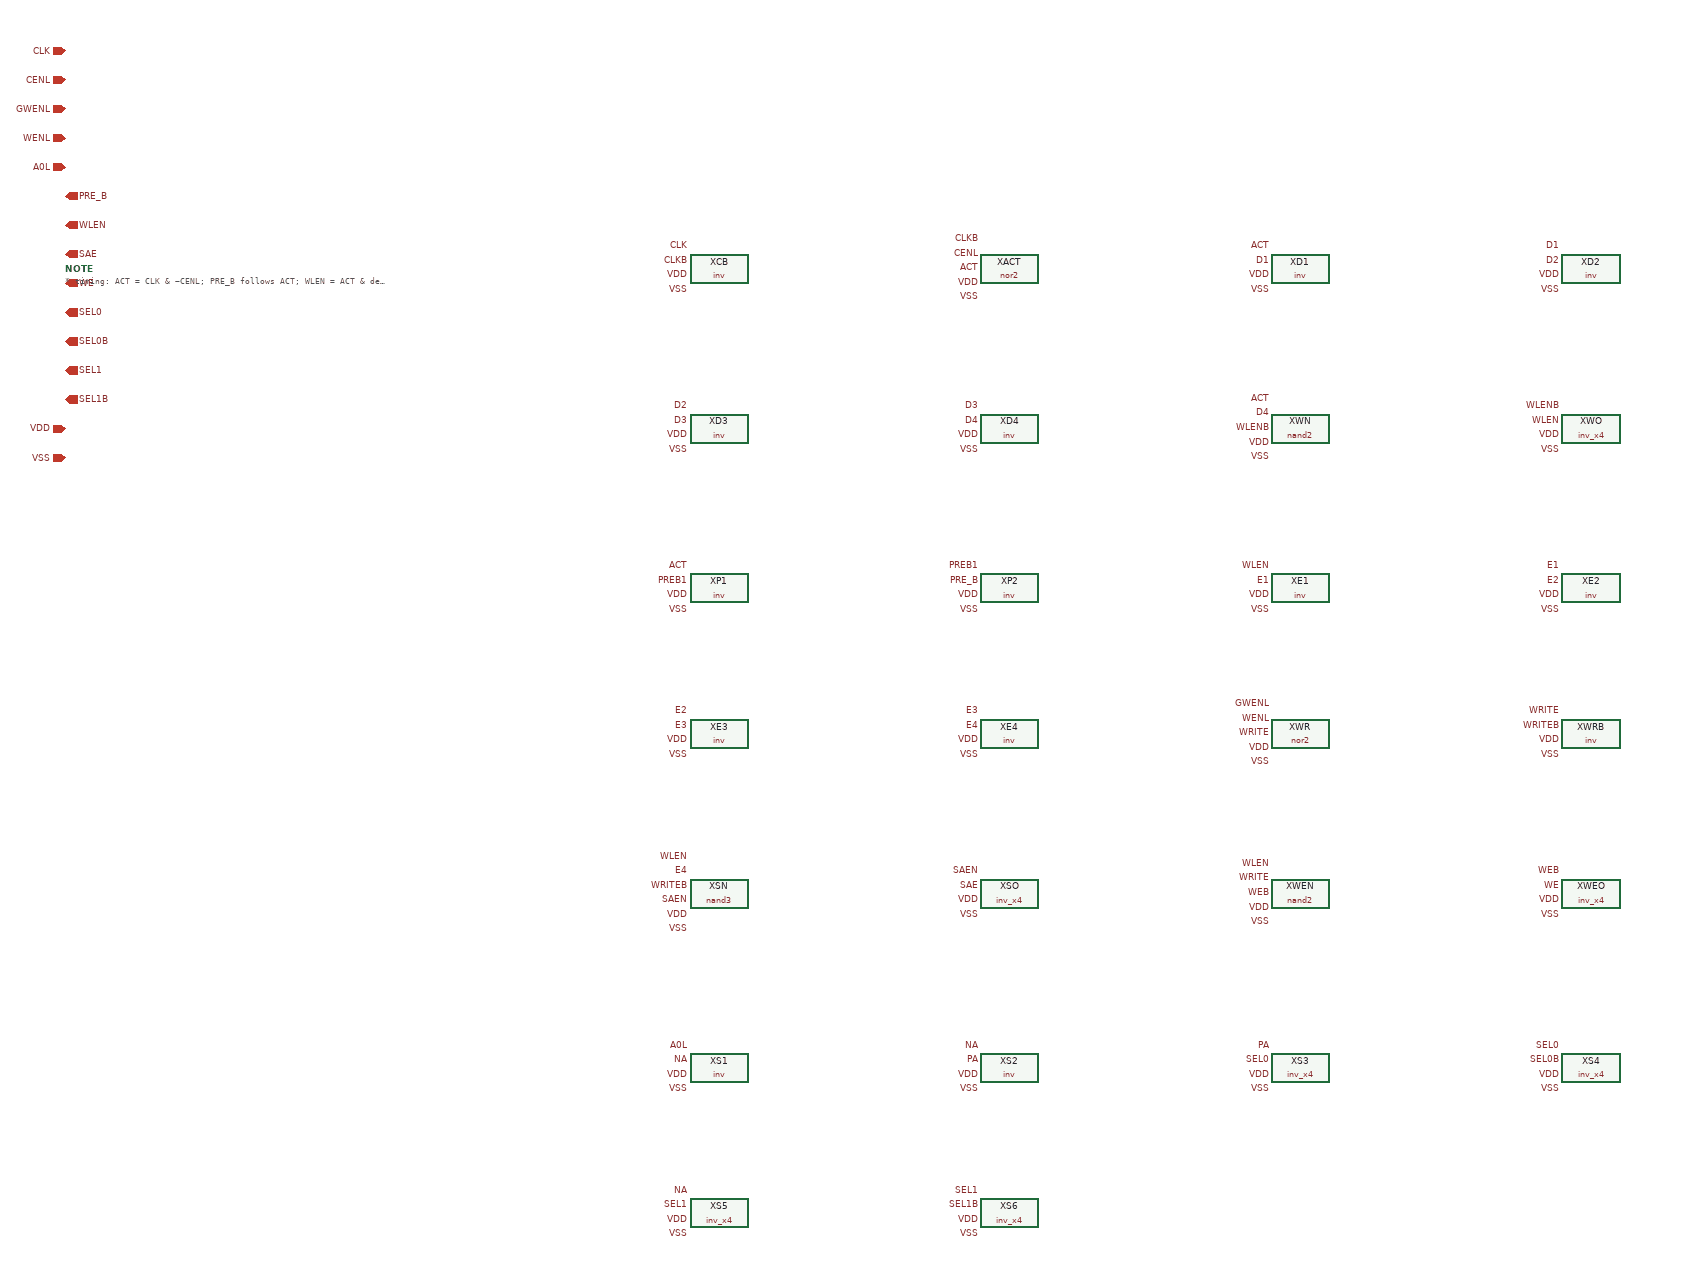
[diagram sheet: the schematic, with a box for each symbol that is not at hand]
v {xschem version=3.4.8RC file_version=1.3}
G {}
K {}
V {}
S {}
E {}
C {gates/inv.sym} 0 0 0 0 {name=XCB}
C {devices/lab_pin.sym} -40.0 -30.0 0 0 {name=l0 lab=CLK}
C {devices/lab_pin.sym} -40.0 -10.0 0 0 {name=l1 lab=CLKB}
C {devices/lab_pin.sym} -40.0 10.0 0 0 {name=l2 lab=VDD}
C {devices/lab_pin.sym} -40.0 30.0 0 0 {name=l3 lab=VSS}
C {gates/nor2.sym} 400 0 0 0 {name=XACT}
C {devices/lab_pin.sym} 360.0 -40.0 0 0 {name=l4 lab=CLKB}
C {devices/lab_pin.sym} 360.0 -20.0 0 0 {name=l5 lab=CENL}
C {devices/lab_pin.sym} 360.0 0.0 0 0 {name=l6 lab=ACT}
C {devices/lab_pin.sym} 360.0 20.0 0 0 {name=l7 lab=VDD}
C {devices/lab_pin.sym} 360.0 40.0 0 0 {name=l8 lab=VSS}
C {gates/inv.sym} 800 0 0 0 {name=XD1}
C {devices/lab_pin.sym} 760.0 -30.0 0 0 {name=l9 lab=ACT}
C {devices/lab_pin.sym} 760.0 -10.0 0 0 {name=l10 lab=D1}
C {devices/lab_pin.sym} 760.0 10.0 0 0 {name=l11 lab=VDD}
C {devices/lab_pin.sym} 760.0 30.0 0 0 {name=l12 lab=VSS}
C {gates/inv.sym} 1200 0 0 0 {name=XD2}
C {devices/lab_pin.sym} 1160.0 -30.0 0 0 {name=l13 lab=D1}
C {devices/lab_pin.sym} 1160.0 -10.0 0 0 {name=l14 lab=D2}
C {devices/lab_pin.sym} 1160.0 10.0 0 0 {name=l15 lab=VDD}
C {devices/lab_pin.sym} 1160.0 30.0 0 0 {name=l16 lab=VSS}
C {gates/inv.sym} 0 220 0 0 {name=XD3}
C {devices/lab_pin.sym} -40.0 190.0 0 0 {name=l17 lab=D2}
C {devices/lab_pin.sym} -40.0 210.0 0 0 {name=l18 lab=D3}
C {devices/lab_pin.sym} -40.0 230.0 0 0 {name=l19 lab=VDD}
C {devices/lab_pin.sym} -40.0 250.0 0 0 {name=l20 lab=VSS}
C {gates/inv.sym} 400 220 0 0 {name=XD4}
C {devices/lab_pin.sym} 360.0 190.0 0 0 {name=l21 lab=D3}
C {devices/lab_pin.sym} 360.0 210.0 0 0 {name=l22 lab=D4}
C {devices/lab_pin.sym} 360.0 230.0 0 0 {name=l23 lab=VDD}
C {devices/lab_pin.sym} 360.0 250.0 0 0 {name=l24 lab=VSS}
C {gates/nand2.sym} 800 220 0 0 {name=XWN}
C {devices/lab_pin.sym} 760.0 180.0 0 0 {name=l25 lab=ACT}
C {devices/lab_pin.sym} 760.0 200.0 0 0 {name=l26 lab=D4}
C {devices/lab_pin.sym} 760.0 220.0 0 0 {name=l27 lab=WLENB}
C {devices/lab_pin.sym} 760.0 240.0 0 0 {name=l28 lab=VDD}
C {devices/lab_pin.sym} 760.0 260.0 0 0 {name=l29 lab=VSS}
C {gates/inv_x4.sym} 1200 220 0 0 {name=XWO}
C {devices/lab_pin.sym} 1160.0 190.0 0 0 {name=l30 lab=WLENB}
C {devices/lab_pin.sym} 1160.0 210.0 0 0 {name=l31 lab=WLEN}
C {devices/lab_pin.sym} 1160.0 230.0 0 0 {name=l32 lab=VDD}
C {devices/lab_pin.sym} 1160.0 250.0 0 0 {name=l33 lab=VSS}
C {gates/inv.sym} 0 440 0 0 {name=XP1}
C {devices/lab_pin.sym} -40.0 410.0 0 0 {name=l34 lab=ACT}
C {devices/lab_pin.sym} -40.0 430.0 0 0 {name=l35 lab=PREB1}
C {devices/lab_pin.sym} -40.0 450.0 0 0 {name=l36 lab=VDD}
C {devices/lab_pin.sym} -40.0 470.0 0 0 {name=l37 lab=VSS}
C {gates/inv.sym} 400 440 0 0 {name=XP2}
C {devices/lab_pin.sym} 360.0 410.0 0 0 {name=l38 lab=PREB1}
C {devices/lab_pin.sym} 360.0 430.0 0 0 {name=l39 lab=PRE_B}
C {devices/lab_pin.sym} 360.0 450.0 0 0 {name=l40 lab=VDD}
C {devices/lab_pin.sym} 360.0 470.0 0 0 {name=l41 lab=VSS}
C {gates/inv.sym} 800 440 0 0 {name=XE1}
C {devices/lab_pin.sym} 760.0 410.0 0 0 {name=l42 lab=WLEN}
C {devices/lab_pin.sym} 760.0 430.0 0 0 {name=l43 lab=E1}
C {devices/lab_pin.sym} 760.0 450.0 0 0 {name=l44 lab=VDD}
C {devices/lab_pin.sym} 760.0 470.0 0 0 {name=l45 lab=VSS}
C {gates/inv.sym} 1200 440 0 0 {name=XE2}
C {devices/lab_pin.sym} 1160.0 410.0 0 0 {name=l46 lab=E1}
C {devices/lab_pin.sym} 1160.0 430.0 0 0 {name=l47 lab=E2}
C {devices/lab_pin.sym} 1160.0 450.0 0 0 {name=l48 lab=VDD}
C {devices/lab_pin.sym} 1160.0 470.0 0 0 {name=l49 lab=VSS}
C {gates/inv.sym} 0 640 0 0 {name=XE3}
C {devices/lab_pin.sym} -40.0 610.0 0 0 {name=l50 lab=E2}
C {devices/lab_pin.sym} -40.0 630.0 0 0 {name=l51 lab=E3}
C {devices/lab_pin.sym} -40.0 650.0 0 0 {name=l52 lab=VDD}
C {devices/lab_pin.sym} -40.0 670.0 0 0 {name=l53 lab=VSS}
C {gates/inv.sym} 400 640 0 0 {name=XE4}
C {devices/lab_pin.sym} 360.0 610.0 0 0 {name=l54 lab=E3}
C {devices/lab_pin.sym} 360.0 630.0 0 0 {name=l55 lab=E4}
C {devices/lab_pin.sym} 360.0 650.0 0 0 {name=l56 lab=VDD}
C {devices/lab_pin.sym} 360.0 670.0 0 0 {name=l57 lab=VSS}
C {gates/nor2.sym} 800 640 0 0 {name=XWR}
C {devices/lab_pin.sym} 760.0 600.0 0 0 {name=l58 lab=GWENL}
C {devices/lab_pin.sym} 760.0 620.0 0 0 {name=l59 lab=WENL}
C {devices/lab_pin.sym} 760.0 640.0 0 0 {name=l60 lab=WRITE}
C {devices/lab_pin.sym} 760.0 660.0 0 0 {name=l61 lab=VDD}
C {devices/lab_pin.sym} 760.0 680.0 0 0 {name=l62 lab=VSS}
C {gates/inv.sym} 1200 640 0 0 {name=XWRB}
C {devices/lab_pin.sym} 1160.0 610.0 0 0 {name=l63 lab=WRITE}
C {devices/lab_pin.sym} 1160.0 630.0 0 0 {name=l64 lab=WRITEB}
C {devices/lab_pin.sym} 1160.0 650.0 0 0 {name=l65 lab=VDD}
C {devices/lab_pin.sym} 1160.0 670.0 0 0 {name=l66 lab=VSS}
C {gates/nand3.sym} 0 860 0 0 {name=XSN}
C {devices/lab_pin.sym} -40.0 810.0 0 0 {name=l67 lab=WLEN}
C {devices/lab_pin.sym} -40.0 830.0 0 0 {name=l68 lab=E4}
C {devices/lab_pin.sym} -40.0 850.0 0 0 {name=l69 lab=WRITEB}
C {devices/lab_pin.sym} -40.0 870.0 0 0 {name=l70 lab=SAEN}
C {devices/lab_pin.sym} -40.0 890.0 0 0 {name=l71 lab=VDD}
C {devices/lab_pin.sym} -40.0 910.0 0 0 {name=l72 lab=VSS}
C {gates/inv_x4.sym} 400 860 0 0 {name=XSO}
C {devices/lab_pin.sym} 360.0 830.0 0 0 {name=l73 lab=SAEN}
C {devices/lab_pin.sym} 360.0 850.0 0 0 {name=l74 lab=SAE}
C {devices/lab_pin.sym} 360.0 870.0 0 0 {name=l75 lab=VDD}
C {devices/lab_pin.sym} 360.0 890.0 0 0 {name=l76 lab=VSS}
C {gates/nand2.sym} 800 860 0 0 {name=XWEN}
C {devices/lab_pin.sym} 760.0 820.0 0 0 {name=l77 lab=WLEN}
C {devices/lab_pin.sym} 760.0 840.0 0 0 {name=l78 lab=WRITE}
C {devices/lab_pin.sym} 760.0 860.0 0 0 {name=l79 lab=WEB}
C {devices/lab_pin.sym} 760.0 880.0 0 0 {name=l80 lab=VDD}
C {devices/lab_pin.sym} 760.0 900.0 0 0 {name=l81 lab=VSS}
C {gates/inv_x4.sym} 1200 860 0 0 {name=XWEO}
C {devices/lab_pin.sym} 1160.0 830.0 0 0 {name=l82 lab=WEB}
C {devices/lab_pin.sym} 1160.0 850.0 0 0 {name=l83 lab=WE}
C {devices/lab_pin.sym} 1160.0 870.0 0 0 {name=l84 lab=VDD}
C {devices/lab_pin.sym} 1160.0 890.0 0 0 {name=l85 lab=VSS}
C {gates/inv.sym} 0 1100 0 0 {name=XS1}
C {devices/lab_pin.sym} -40.0 1070.0 0 0 {name=l86 lab=A0L}
C {devices/lab_pin.sym} -40.0 1090.0 0 0 {name=l87 lab=NA}
C {devices/lab_pin.sym} -40.0 1110.0 0 0 {name=l88 lab=VDD}
C {devices/lab_pin.sym} -40.0 1130.0 0 0 {name=l89 lab=VSS}
C {gates/inv.sym} 400 1100 0 0 {name=XS2}
C {devices/lab_pin.sym} 360.0 1070.0 0 0 {name=l90 lab=NA}
C {devices/lab_pin.sym} 360.0 1090.0 0 0 {name=l91 lab=PA}
C {devices/lab_pin.sym} 360.0 1110.0 0 0 {name=l92 lab=VDD}
C {devices/lab_pin.sym} 360.0 1130.0 0 0 {name=l93 lab=VSS}
C {gates/inv_x4.sym} 800 1100 0 0 {name=XS3}
C {devices/lab_pin.sym} 760.0 1070.0 0 0 {name=l94 lab=PA}
C {devices/lab_pin.sym} 760.0 1090.0 0 0 {name=l95 lab=SEL0}
C {devices/lab_pin.sym} 760.0 1110.0 0 0 {name=l96 lab=VDD}
C {devices/lab_pin.sym} 760.0 1130.0 0 0 {name=l97 lab=VSS}
C {gates/inv_x4.sym} 1200 1100 0 0 {name=XS4}
C {devices/lab_pin.sym} 1160.0 1070.0 0 0 {name=l98 lab=SEL0}
C {devices/lab_pin.sym} 1160.0 1090.0 0 0 {name=l99 lab=SEL0B}
C {devices/lab_pin.sym} 1160.0 1110.0 0 0 {name=l100 lab=VDD}
C {devices/lab_pin.sym} 1160.0 1130.0 0 0 {name=l101 lab=VSS}
C {gates/inv_x4.sym} 0 1300 0 0 {name=XS5}
C {devices/lab_pin.sym} -40.0 1270.0 0 0 {name=l102 lab=NA}
C {devices/lab_pin.sym} -40.0 1290.0 0 0 {name=l103 lab=SEL1}
C {devices/lab_pin.sym} -40.0 1310.0 0 0 {name=l104 lab=VDD}
C {devices/lab_pin.sym} -40.0 1330.0 0 0 {name=l105 lab=VSS}
C {gates/inv_x4.sym} 400 1300 0 0 {name=XS6}
C {devices/lab_pin.sym} 360.0 1270.0 0 0 {name=l106 lab=SEL1}
C {devices/lab_pin.sym} 360.0 1290.0 0 0 {name=l107 lab=SEL1B}
C {devices/lab_pin.sym} 360.0 1310.0 0 0 {name=l108 lab=VDD}
C {devices/lab_pin.sym} 360.0 1330.0 0 0 {name=l109 lab=VSS}
C {devices/ipin.sym} -900 -300 0 0 {name=p110 lab=CLK}
C {devices/ipin.sym} -900 -260 0 0 {name=p111 lab=CENL}
C {devices/ipin.sym} -900 -220 0 0 {name=p112 lab=GWENL}
C {devices/ipin.sym} -900 -180 0 0 {name=p113 lab=WENL}
C {devices/ipin.sym} -900 -140 0 0 {name=p114 lab=A0L}
C {devices/opin.sym} -900 -100 0 0 {name=p115 lab=PRE_B}
C {devices/opin.sym} -900 -60 0 0 {name=p116 lab=WLEN}
C {devices/opin.sym} -900 -20 0 0 {name=p117 lab=SAE}
C {devices/opin.sym} -900 20 0 0 {name=p118 lab=WE}
C {devices/opin.sym} -900 60 0 0 {name=p119 lab=SEL0}
C {devices/opin.sym} -900 100 0 0 {name=p120 lab=SEL0B}
C {devices/opin.sym} -900 140 0 0 {name=p121 lab=SEL1}
C {devices/opin.sym} -900 180 0 0 {name=p122 lab=SEL1B}
C {devices/iopin.sym} -900 220 0 0 {name=p123 lab=VDD}
C {devices/iopin.sym} -900 260 0 0 {name=p124 lab=VSS}
C {devices/code_shown.sym} -900 0 0 0 {name=NOTE only_toplevel=false
place=header
value="* timing: ACT = CLK & ~CENL; PRE_B follows ACT; WLEN = ACT & delayed ACT; SAE = WLEN & delayed WLEN & read; WE = WLEN & write; SEL* from A0L"}
